One B-rep face of a CAD part: STEP entity #123.
In plain terms, the planar face has unit normal (0, 0, 1).
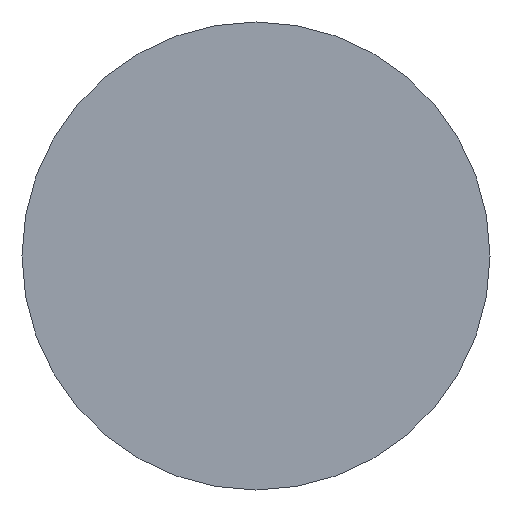
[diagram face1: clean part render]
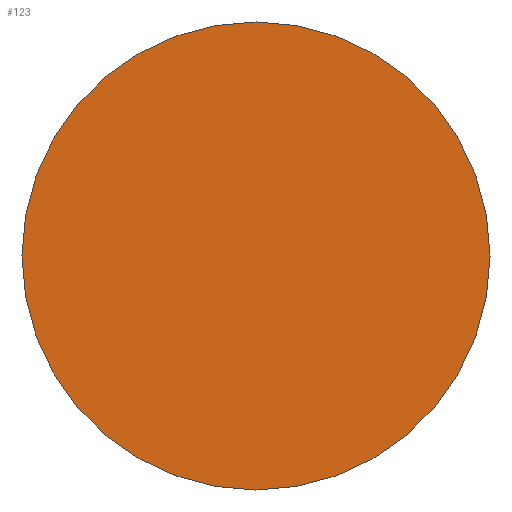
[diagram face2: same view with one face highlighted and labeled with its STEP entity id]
Its self-contained STEP definition (entity closure, numbers rounded to 3 decimals):
#39 = EDGE_CURVE('',#40,#40,#42,.T.);
#40 = VERTEX_POINT('',#41);
#41 = CARTESIAN_POINT('',(4.,0.,77.));
#42 = SURFACE_CURVE('',#43,(#48,#60),.PCURVE_S1.);
#43 = CIRCLE('',#44,4.);
#44 = AXIS2_PLACEMENT_3D('',#45,#46,#47);
#45 = CARTESIAN_POINT('',(0.,0.,77.));
#46 = DIRECTION('',(0.,0.,1.));
#47 = DIRECTION('',(1.,0.,-0.));
#48 = PCURVE('',#49,#54);
#49 = CYLINDRICAL_SURFACE('',#50,4.);
#50 = AXIS2_PLACEMENT_3D('',#51,#52,#53);
#51 = CARTESIAN_POINT('',(0.,0.,-77.));
#52 = DIRECTION('',(0.,0.,1.));
#53 = DIRECTION('',(1.,0.,-0.));
#54 = DEFINITIONAL_REPRESENTATION('',(#55),#59);
#55 = LINE('',#56,#57);
#56 = CARTESIAN_POINT('',(0.,154.));
#57 = VECTOR('',#58,1.);
#58 = DIRECTION('',(1.,0.));
#59 = ( GEOMETRIC_REPRESENTATION_CONTEXT(2) 
PARAMETRIC_REPRESENTATION_CONTEXT() REPRESENTATION_CONTEXT('2D SPACE',''
  ) );
#60 = PCURVE('',#61,#66);
#61 = PLANE('',#62);
#62 = AXIS2_PLACEMENT_3D('',#63,#64,#65);
#63 = CARTESIAN_POINT('',(0.,0.,77.));
#64 = DIRECTION('',(0.,0.,1.));
#65 = DIRECTION('',(1.,0.,-0.));
#66 = DEFINITIONAL_REPRESENTATION('',(#67),#71);
#67 = CIRCLE('',#68,4.);
#68 = AXIS2_PLACEMENT_2D('',#69,#70);
#69 = CARTESIAN_POINT('',(0.,0.));
#70 = DIRECTION('',(1.,0.));
#71 = ( GEOMETRIC_REPRESENTATION_CONTEXT(2) 
PARAMETRIC_REPRESENTATION_CONTEXT() REPRESENTATION_CONTEXT('2D SPACE',''
  ) );
#123 = ADVANCED_FACE('',(#124),#61,.T.);
#124 = FACE_BOUND('',#125,.T.);
#125 = EDGE_LOOP('',(#126));
#126 = ORIENTED_EDGE('',*,*,#39,.T.);
